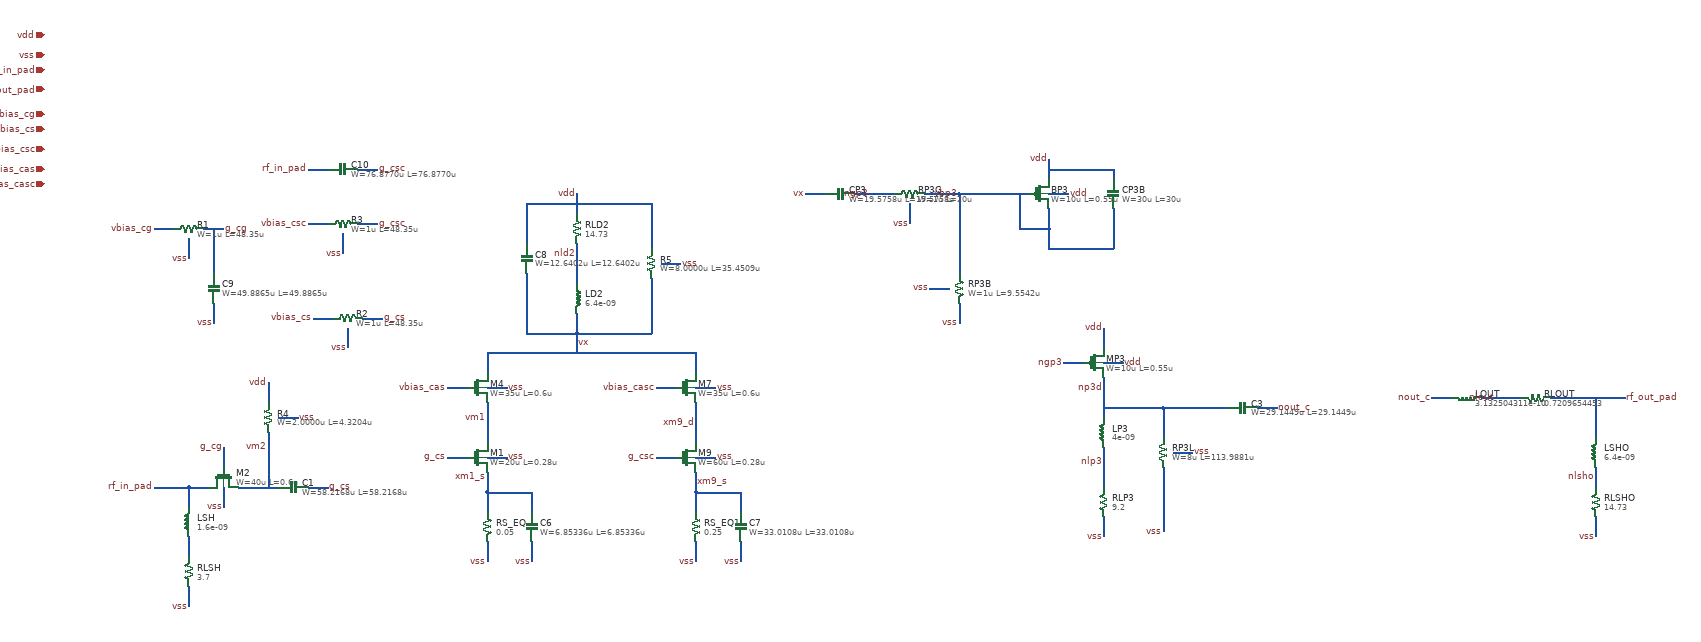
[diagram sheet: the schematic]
v {xschem version=3.4.8RC file_version=1.3}
G {}
K {}
V {}
S {}
F {}
E {}
N 330 -270 330 -230 {lab=#net1}
N 330 -370 330 -330 {lab=rf_in_pad}
N 330 -170 330 -130 {lab=vss}
N 430 -370 470 -370 {lab=vm2}
N 400 -450 400 -410 {lab=g_cg}
N 330 -370 370 -370 {lab=rf_in_pad}
N 400 -370 400 -330 {lab=vss}
N 260 -890 300 -890 {lab=vbias_cg}
N 360 -890 400 -890 {lab=g_cg}
N 330 -870 330 -830 {lab=vss}
N 380 -740 380 -700 {lab=vss}
N 380 -840 380 -800 {lab=g_cg}
N 490 -480 490 -440 {lab=vm2}
N 490 -580 490 -540 {lab=vdd}
N 510 -510 550 -510 {lab=vss}
N 570 -370 610 -370 {lab=g_cs}
N 470 -370 510 -370 {lab=vm2}
N 580 -710 620 -710 {lab=vbias_cs}
N 680 -710 720 -710 {lab=g_cs}
N 650 -690 650 -650 {lab=vss}
N 930 -500 930 -460 {lab=vm1}
N 850 -430 890 -430 {lab=g_cs}
N 930 -400 930 -360 {lab=xm1_s}
N 930 -430 970 -430 {lab=vss}
N 930 -360 930 -320 {lab=xm1_s}
N 930 -260 930 -220 {lab=vss}
N 1020 -360 1020 -320 {lab=xm1_s}
N 1020 -260 1020 -220 {lab=vss}
N 930 -640 930 -600 {lab=vx}
N 850 -570 890 -570 {lab=vbias_cas}
N 930 -540 930 -500 {lab=vm1}
N 930 -570 970 -570 {lab=vss}
N 570 -1010 610 -1010 {lab=rf_in_pad}
N 670 -1010 710 -1010 {lab=g_csc}
N 570 -900 610 -900 {lab=vbias_csc}
N 670 -900 710 -900 {lab=g_csc}
N 640 -880 640 -840 {lab=vss}
N 1350 -500 1350 -460 {lab=xm9_d}
N 1270 -430 1310 -430 {lab=g_csc}
N 1350 -400 1350 -360 {lab=xm9_s}
N 1350 -430 1390 -430 {lab=vss}
N 1350 -360 1350 -320 {lab=xm9_s}
N 1350 -260 1350 -220 {lab=vss}
N 1440 -360 1440 -320 {lab=xm9_s}
N 1440 -260 1440 -220 {lab=vss}
N 1350 -640 1350 -600 {lab=vx}
N 1270 -570 1310 -570 {lab=vbias_casc}
N 1350 -540 1350 -500 {lab=xm9_d}
N 1350 -570 1390 -570 {lab=vss}
N 1110 -820 1110 -780 {lab=nld2}
N 1110 -720 1110 -680 {lab=vx}
N 1110 -960 1110 -920 {lab=vdd}
N 1110 -860 1110 -820 {lab=nld2}
N 1260 -790 1260 -750 {lab=vx}
N 1260 -890 1260 -850 {lab=vdd}
N 1280 -820 1320 -820 {lab=vss}
N 1010 -900 1010 -860 {lab=vdd}
N 1010 -800 1010 -760 {lab=vx}
N 1670 -960 1710 -960 {lab=ngp3}
N 1570 -960 1610 -960 {lab=vx}
N 1710 -960 1750 -960 {lab=ngp3}
N 1810 -960 1850 -960 {lab=vbp3}
N 1780 -940 1780 -900 {lab=vss}
N 2060 -930 2060 -890 {lab=vbp3}
N 1980 -960 2020 -960 {lab=vbp3}
N 2060 -1030 2060 -990 {lab=vdd}
N 2060 -960 2100 -960 {lab=vdd}
N 1880 -840 1880 -800 {lab=vbp3}
N 1880 -740 1880 -700 {lab=vss}
N 1820 -770 1860 -770 {lab=vss}
N 2060 -890 2060 -850 {lab=vbp3}
N 2170 -590 2170 -550 {lab=np3d}
N 2090 -620 2130 -620 {lab=ngp3}
N 2170 -690 2170 -650 {lab=vdd}
N 2170 -620 2210 -620 {lab=vdd}
N 2170 -450 2170 -410 {lab=nlp3}
N 2170 -550 2170 -510 {lab=np3d}
N 2170 -310 2170 -270 {lab=vss}
N 2170 -410 2170 -370 {lab=nlp3}
N 2290 -510 2290 -470 {lab=np3d}
N 2290 -410 2290 -370 {lab=vss}
N 2310 -440 2350 -440 {lab=vss}
N 2480 -530 2520 -530 {lab=nout_c}
N 2380 -530 2420 -530 {lab=np3d}
N 2930 -550 2970 -550 {lab=nlout}
N 2830 -550 2870 -550 {lab=nout_c}
N 3070 -550 3110 -550 {lab=rf_out_pad}
N 2970 -550 3010 -550 {lab=nlout}
N 3160 -410 3160 -370 {lab=nlsho}
N 3160 -310 3160 -270 {lab=vss}
N 380 -890 380 -840 {lab=g_cg}
N 490 -440 490 -370 {lab=vm2}
N 930 -360 1020 -360 {lab=xm1_s}
N 1350 -360 1440 -360 {lab=xm9_s}
N 2290 -530 2290 -510 {lab=np3d}
N 2170 -530 2290 -530 {lab=np3d}
N 2290 -370 2290 -280 {lab=vss}
N 2290 -530 2380 -530 {lab=np3d}
N 260 -370 330 -370 {lab=rf_in_pad}
N 930 -640 1350 -640 {lab=vx}
N 1110 -680 1110 -640 {lab=vx}
N 1010 -940 1010 -900 {lab=vdd}
N 1010 -940 1110 -940 {lab=vdd}
N 1010 -760 1010 -680 {lab=vx}
N 1010 -680 1110 -680 {lab=vx}
N 1260 -940 1260 -890 {lab=vdd}
N 1110 -940 1260 -940 {lab=vdd}
N 1260 -750 1260 -680 {lab=vx}
N 1110 -680 1260 -680 {lab=vx}
N 2000 -890 2060 -890 {lab=vbp3}
N 2000 -960 2000 -890 {lab=vbp3}
N 2190 -1010 2190 -990 {lab=vdd}
N 2060 -1010 2190 -1010 {lab=vdd}
N 2190 -930 2190 -850 {lab=vbp3}
N 2060 -850 2190 -850 {lab=vbp3}
N 1850 -960 1880 -960 {lab=vbp3}
N 1880 -960 1880 -840 {lab=vbp3}
N 1880 -960 1980 -960 {lab=vbp3}
N 3110 -550 3170 -550 {lab=rf_out_pad}
N 3160 -550 3160 -470 {lab=rf_out_pad}
N 3170 -550 3220 -550 {lab=rf_out_pad}
C {iopin.sym} 40 -1280 0 0 {name=p1 lab=vdd}
C {iopin.sym} 40 -1240 0 0 {name=p2 lab=vss}
C {iopin.sym} 40 -1210 0 0 {name=p3 lab=rf_in_pad}
C {iopin.sym} 40 -1170 0 0 {name=p4 lab=rf_out_pad}
C {iopin.sym} 40 -1120 0 0 {name=p5 lab=vbias_cg}
C {iopin.sym} 40 -1090 0 0 {name=p6 lab=vbias_cs}
C {iopin.sym} 40 -1050 0 0 {name=p7 lab=vbias_csc}
C {iopin.sym} 40 -1010 0 0 {name=p8 lab=vbias_cas}
C {iopin.sym} 40 -980 0 0 {name=p9 lab=vbias_casc}
C {ind.sym} 330 -300 2 0 {name=LSH
m=1
value=1.6e-09
}
C {lab_pin.sym} 260 -370 0 0 {name=l11 sig_type=std_logic lab=rf_in_pad}
C {res.sym} 330 -200 2 0 {name=RLSH
value=3.7
m=1
}
C {lab_pin.sym} 330 -130 3 0 {name=l12 sig_type=std_logic lab=vss}
C {symbols/nfet_05v0.sym} 400 -390 1 0 {name=M2
L=0.6u
W=40u
nf=10
m=1
ad="'int((nf+1)/2) * W/nf * 0.18u'"
pd="'2*int((nf+1)/2) * (W/nf + 0.18u)'"
as="'int((nf+2)/2) * W/nf * 0.18u'"
ps="'2*int((nf+2)/2) * (W/nf + 0.18u)'"
nrd="'0.18u / W'"
nrs="'0.18u / W'"
sa=0
sb=0
sd=0
model=nfet_05v0
spiceprefix=X
}
C {lab_pin.sym} 400 -450 1 0 {name=l15 sig_type=std_logic lab=g_cg}
C {lab_pin.sym} 550 -510 2 0 {name=l17 sig_type=std_logic lab=vss}
C {symbols/ppolyf_u_1k.sym} 330 -890 3 0 {name=R1
W=1u
L=48.35u
model=ppolyf_u_1k
spiceprefix=X
m=1
}
C {lab_pin.sym} 260 -890 0 0 {name=l18 sig_type=std_logic lab=vbias_cg}
C {lab_pin.sym} 400 -890 2 0 {name=l19 sig_type=std_logic lab=g_cg}
C {lab_pin.sym} 330 -830 3 0 {name=l20 sig_type=std_logic lab=vss}
C {symbols/cap_mim_2f0fF.sym} 380 -770 2 0 {name=C9
W=49.8865u
L=49.8865u
model=cap_mim_2f0_m4m5_noshield
spiceprefix=X
m=4
}
C {lab_pin.sym} 380 -700 3 0 {name=l21 sig_type=std_logic lab=vss}
C {symbols/ppolyf_u.sym} 490 -510 2 0 {name=R4
W=2.0000u
L=4.3204u
model=ppolyf_u
spiceprefix=X
m=1
}
C {lab_pin.sym} 490 -580 1 0 {name=l24 sig_type=std_logic lab=vdd}
C {lab_pin.sym} 400 -330 3 0 {name=l25 sig_type=std_logic lab=vss}
C {symbols/cap_mim_2f0fF.sym} 540 -370 1 0 {name=C1
W=58.2168u
L=58.2168u
model=cap_mim_2f0_m4m5_noshield
spiceprefix=X
m=1
}
C {lab_pin.sym} 610 -370 2 0 {name=l26 sig_type=std_logic lab=g_cs}
C {symbols/ppolyf_u_1k.sym} 650 -710 3 0 {name=R2
W=1u
L=48.35u
model=ppolyf_u_1k
spiceprefix=X
m=1
}
C {lab_pin.sym} 580 -710 0 0 {name=l28 sig_type=std_logic lab=vbias_cs}
C {lab_pin.sym} 720 -710 2 0 {name=l29 sig_type=std_logic lab=g_cs}
C {lab_pin.sym} 650 -650 3 0 {name=l30 sig_type=std_logic lab=vss}
C {symbols/nfet_03v3.sym} 910 -430 0 0 {name=M1
L=0.28u
W=20u
nf=10
m=2
ad="'int((nf+1)/2) * W/nf * 0.18u'"
pd="'2*int((nf+1)/2) * (W/nf + 0.18u)'"
as="'int((nf+2)/2) * W/nf * 0.18u'"
ps="'2*int((nf+2)/2) * (W/nf + 0.18u)'"
nrd="'0.18u / W'"
nrs="'0.18u / W'"
sa=0
sb=0
sd=0
model=nfet_03v3
spiceprefix=X
}
C {lab_pin.sym} 850 -430 0 0 {name=l32 sig_type=std_logic lab=g_cs}
C {lab_pin.sym} 930 -390 0 0 {name=l33 sig_type=std_logic lab=xm1_s}
C {lab_pin.sym} 970 -430 2 0 {name=l34 sig_type=std_logic lab=vss}
C {res.sym} 930 -290 0 0 {name=RS_EQ
value=0.05
m=1
}
C {lab_pin.sym} 930 -220 3 0 {name=l36 sig_type=std_logic lab=vss}
C {symbols/cap_mim_2f0fF.sym} 1020 -290 0 0 {name=C6
W=6.85336u
L=6.85336u
model=cap_mim_2f0_m4m5_noshield
spiceprefix=X
m=1
}
C {lab_pin.sym} 1020 -220 3 0 {name=l38 sig_type=std_logic lab=vss}
C {symbols/nfet_05v0.sym} 910 -570 0 0 {name=M4
L=0.6u
W=35u
nf=10
m=1
ad="'int((nf+1)/2) * W/nf * 0.18u'"
pd="'2*int((nf+1)/2) * (W/nf + 0.18u)'"
as="'int((nf+2)/2) * W/nf * 0.18u'"
ps="'2*int((nf+2)/2) * (W/nf + 0.18u)'"
nrd="'0.18u / W'"
nrs="'0.18u / W'"
sa=0
sb=0
sd=0
model=nfet_05v0
spiceprefix=X
}
C {lab_pin.sym} 1110 -660 2 0 {name=l39 sig_type=std_logic lab=vx}
C {lab_pin.sym} 850 -570 0 0 {name=l40 sig_type=std_logic lab=vbias_cas}
C {lab_pin.sym} 930 -510 0 0 {name=l41 sig_type=std_logic lab=vm1}
C {lab_pin.sym} 970 -570 2 0 {name=l42 sig_type=std_logic lab=vss}
C {symbols/cap_mim_2f0fF.sym} 640 -1010 3 0 {name=C10
W=76.8770u
L=76.8770u
model=cap_mim_2f0_m4m5_noshield
spiceprefix=X
m=1
}
C {lab_pin.sym} 570 -1010 0 0 {name=l43 sig_type=std_logic lab=rf_in_pad}
C {lab_pin.sym} 710 -1010 2 0 {name=l44 sig_type=std_logic lab=g_csc}
C {symbols/ppolyf_u_1k.sym} 640 -900 3 0 {name=R3
W=1u
L=48.35u
model=ppolyf_u_1k
spiceprefix=X
m=1
}
C {lab_pin.sym} 570 -900 0 0 {name=l45 sig_type=std_logic lab=vbias_csc}
C {lab_pin.sym} 710 -900 2 0 {name=l46 sig_type=std_logic lab=g_csc}
C {lab_pin.sym} 640 -840 3 0 {name=l47 sig_type=std_logic lab=vss}
C {symbols/nfet_03v3.sym} 1330 -430 0 0 {name=M9
L=0.28u
W=60u
nf=4
m=8
ad="'int((nf+1)/2) * W/nf * 0.18u'"
pd="'2*int((nf+1)/2) * (W/nf + 0.18u)'"
as="'int((nf+2)/2) * W/nf * 0.18u'"
ps="'2*int((nf+2)/2) * (W/nf + 0.18u)'"
nrd="'0.18u / W'"
nrs="'0.18u / W'"
sa=0
sb=0
sd=0
model=nfet_03v3
spiceprefix=X
}
C {lab_pin.sym} 1270 -430 0 0 {name=l49 sig_type=std_logic lab=g_csc}
C {lab_pin.sym} 1350 -380 2 0 {name=l50 sig_type=std_logic lab=xm9_s}
C {lab_pin.sym} 1390 -430 2 0 {name=l51 sig_type=std_logic lab=vss}
C {res.sym} 1350 -290 0 0 {name=RS_EQ1
value=0.25
m=1
}
C {lab_pin.sym} 1350 -220 3 0 {name=l53 sig_type=std_logic lab=vss}
C {symbols/cap_mim_2f0fF.sym} 1440 -290 0 0 {name=C7
W=33.0108u
L=33.0108u
model=cap_mim_2f0_m4m5_noshield
spiceprefix=X
m=1
}
C {lab_pin.sym} 1440 -220 3 0 {name=l55 sig_type=std_logic lab=vss}
C {symbols/nfet_05v0.sym} 1330 -570 0 0 {name=M7
L=0.6u
W=35u
nf=10
m=4
ad="'int((nf+1)/2) * W/nf * 0.18u'"
pd="'2*int((nf+1)/2) * (W/nf + 0.18u)'"
as="'int((nf+2)/2) * W/nf * 0.18u'"
ps="'2*int((nf+2)/2) * (W/nf + 0.18u)'"
nrd="'0.18u / W'"
nrs="'0.18u / W'"
sa=0
sb=0
sd=0
model=nfet_05v0
spiceprefix=X
}
C {lab_pin.sym} 1270 -570 0 0 {name=l57 sig_type=std_logic lab=vbias_casc}
C {lab_pin.sym} 1350 -500 0 0 {name=l58 sig_type=std_logic lab=xm9_d}
C {lab_pin.sym} 1390 -570 2 0 {name=l59 sig_type=std_logic lab=vss}
C {ind.sym} 1110 -750 0 0 {name=LD2
m=1
value=6.4e-09
}
C {res.sym} 1110 -890 0 0 {name=RLD2
value=14.73
m=1
}
C {lab_pin.sym} 1110 -960 1 0 {name=l62 sig_type=std_logic lab=vdd}
C {lab_pin.sym} 1110 -840 0 0 {name=l63 sig_type=std_logic lab=nld2}
C {symbols/ppolyf_u.sym} 1260 -820 2 0 {name=R5
W=8.0000u
L=35.4509u
model=ppolyf_u
spiceprefix=X
m=1
}
C {lab_pin.sym} 1320 -820 2 0 {name=l66 sig_type=std_logic lab=vss}
C {symbols/cap_mim_2f0fF.sym} 1010 -830 0 1 {name=C8
W=12.6402u
L=12.6402u
model=cap_mim_2f0_m4m5_noshield
spiceprefix=X
m=1
}
C {symbols/cap_mim_2f0fF.sym} 1640 -960 1 0 {name=CP3
W=19.5758u
L=19.5758u
model=cap_mim_2f0_m4m5_noshield
spiceprefix=X
m=1
}
C {lab_pin.sym} 1570 -960 0 0 {name=l70 sig_type=std_logic lab=vx}
C {symbols/ppolyf_u_1k.sym} 1780 -960 3 0 {name=RP3G
W=1u
L=20u
model=ppolyf_u_1k
spiceprefix=X
m=1
}
C {lab_pin.sym} 1700 -960 1 0 {name=l71 sig_type=std_logic lab=ngp3}
C {lab_pin.sym} 1780 -900 3 0 {name=l73 sig_type=std_logic lab=vss}
C {symbols/pfet_06v0.sym} 2040 -960 0 0 {name=BP3
L=0.55u
W=10u
nf=4
m=1
ad="'int((nf+1)/2) * W/nf * 0.18u'"
pd="'2*int((nf+1)/2) * (W/nf + 0.18u)'"
as="'int((nf+2)/2) * W/nf * 0.18u'"
ps="'2*int((nf+2)/2) * (W/nf + 0.18u)'"
nrd="'0.18u / W'"
nrs="'0.18u / W'"
sa=0
sb=0
sd=0
model=pfet_06v0
spiceprefix=X
}
C {lab_pin.sym} 1880 -960 1 0 {name=l75 sig_type=std_logic lab=vbp3}
C {lab_pin.sym} 2060 -1030 1 0 {name=l76 sig_type=std_logic lab=vdd}
C {lab_pin.sym} 2100 -960 2 0 {name=l77 sig_type=std_logic lab=vdd}
C {symbols/ppolyf_u_1k.sym} 1880 -770 0 0 {name=RP3B
W=1u
L=9.5542u
model=ppolyf_u_1k
spiceprefix=X
m=1
}
C {lab_pin.sym} 1880 -700 3 0 {name=l79 sig_type=std_logic lab=vss}
C {lab_pin.sym} 1820 -770 0 0 {name=l80 sig_type=std_logic lab=vss}
C {symbols/cap_mim_2f0fF.sym} 2190 -960 0 0 {name=CP3B
W=30u
L=30u
model=cap_mim_2f0_m4m5_noshield
spiceprefix=X
m=1
}
C {symbols/pfet_06v0.sym} 2150 -620 0 0 {name=MP3
L=0.55u
W=10u
nf=4
m=36
ad="'int((nf+1)/2) * W/nf * 0.18u'"
pd="'2*int((nf+1)/2) * (W/nf + 0.18u)'"
as="'int((nf+2)/2) * W/nf * 0.18u'"
ps="'2*int((nf+2)/2) * (W/nf + 0.18u)'"
nrd="'0.18u / W'"
nrs="'0.18u / W'"
sa=0
sb=0
sd=0
model=pfet_06v0
spiceprefix=X
}
C {lab_pin.sym} 2170 -570 0 0 {name=l83 sig_type=std_logic lab=np3d}
C {lab_pin.sym} 2090 -620 0 0 {name=l84 sig_type=std_logic lab=ngp3}
C {lab_pin.sym} 2170 -690 1 0 {name=l85 sig_type=std_logic lab=vdd}
C {lab_pin.sym} 2210 -620 2 0 {name=l86 sig_type=std_logic lab=vdd}
C {ind.sym} 2170 -480 2 0 {name=LP3
m=1
value=4e-09
}
C {lab_pin.sym} 2170 -420 0 0 {name=l87 sig_type=std_logic lab=nlp3}
C {res.sym} 2170 -340 2 0 {name=RLP3
value=9.2
m=1
}
C {lab_pin.sym} 2170 -270 3 0 {name=l89 sig_type=std_logic lab=vss}
C {symbols/ppolyf_u.sym} 2290 -440 0 1 {name=RP3L
W=8u
L=113.9881u
model=ppolyf_u
spiceprefix=X
m=1
}
C {lab_pin.sym} 2290 -280 3 0 {name=l92 sig_type=std_logic lab=vss}
C {lab_pin.sym} 2350 -440 0 1 {name=l93 sig_type=std_logic lab=vss}
C {symbols/cap_mim_2f0fF.sym} 2450 -530 1 0 {name=C3
W=29.1449u
L=29.1449u
model=cap_mim_2f0_m4m5_noshield
spiceprefix=X
m=1
}
C {lab_pin.sym} 2520 -530 2 0 {name=l94 sig_type=std_logic lab=nout_c}
C {ind.sym} 2900 -550 1 0 {name=LOUT
m=1
value=3.132504311e-10
}
C {lab_pin.sym} 2960 -550 3 0 {name=l96 sig_type=std_logic lab=nlout}
C {lab_pin.sym} 2830 -550 0 0 {name=l97 sig_type=std_logic lab=nout_c}
C {res.sym} 3040 -550 1 0 {name=RLOUT
value=0.7209654453
m=1
}
C {lab_pin.sym} 3220 -550 2 0 {name=l98 sig_type=std_logic lab=rf_out_pad}
C {ind.sym} 3160 -440 2 0 {name=LSHO
m=1
value=6.4e-09
}
C {lab_pin.sym} 3160 -390 0 0 {name=l100 sig_type=std_logic lab=nlsho}
C {res.sym} 3160 -340 2 0 {name=RLSHO
value=14.73
m=1
}
C {lab_pin.sym} 3160 -270 3 0 {name=l102 sig_type=std_logic lab=vss}
C {lab_pin.sym} 490 -450 0 0 {name=l1 sig_type=std_logic lab=vm2}
C {title-2.sym} 0 0 0 0 {name=l2 author="Arjun Ananth" rev=1.0 lock=true
}
